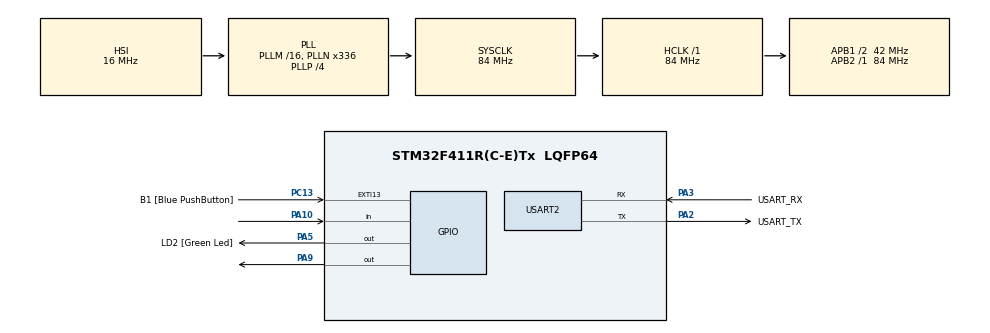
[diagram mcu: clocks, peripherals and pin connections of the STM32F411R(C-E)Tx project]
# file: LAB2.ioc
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Mcu.Family=STM32F4
Mcu.Name=STM32F411R(C-E)Tx
Mcu.Package=LQFP64
NVIC.PriorityGroup=NVIC_PRIORITYGROUP_0
PA10.Signal=GPIO_Input
PA13.GPIO_Label=TMS
PA13.Mode=Serial_Wire
PA13.Signal=SYS_JTMS-SWDIO
PA14.GPIO_Label=TCK
PA14.Mode=Serial_Wire
PA14.Signal=SYS_JTCK-SWCLK
PA2.GPIO_Label=USART_TX
PA2.Mode=Asynchronous
PA2.Signal=USART2_TX
PA3.GPIO_Label=USART_RX
PA3.Mode=Asynchronous
PA3.Signal=USART2_RX
PA5.GPIO_Label=LD2 [Green Led]
PA5.Signal=GPIO_Output
PA9.Signal=GPIO_Output
PB3.GPIO_Label=SWO
PB3.Signal=SYS_JTDO-SWO
PC13-ANTI_TAMP.GPIO_Label=B1 [Blue PushButton]
PC13-ANTI_TAMP.GPIO_ModeDefaultEXTI=GPIO_MODE_IT_FALLING
PC13-ANTI_TAMP.Signal=GPXTI13
PC14-OSC32_IN.Mode=LSE-External-Oscillator
PC14-OSC32_IN.Signal=RCC_OSC32_IN
PC15-OSC32_OUT.Mode=LSE-External-Oscillator
PC15-OSC32_OUT.Signal=RCC_OSC32_OUT
PH0\ -\ OSC_IN.Mode=HSE-External-Clock-Source
PH0\ -\ OSC_IN.Signal=RCC_OSC_IN
PH1\ -\ OSC_OUT.Mode=HSE-External-Clock-Source
PH1\ -\ OSC_OUT.Signal=RCC_OSC_OUT
ProjectManager.HeapSize=0x200
ProjectManager.StackSize=0x400
ProjectManager.TargetToolchain=STM32CubeIDE
RCC.48MHZClocksFreq_Value=84000000
RCC.AHBFreq_Value=84000000
RCC.APB1CLKDivider=RCC_HCLK_DIV2
RCC.APB1Freq_Value=42000000
RCC.APB1TimFreq_Value=84000000
RCC.APB2Freq_Value=84000000
RCC.APB2TimFreq_Value=84000000
RCC.CortexFreq_Value=84000000
RCC.FLatency-AdvancedSettings=FLASH_LATENCY_2
RCC.HCLKFreq_Value=84000000
RCC.HSE_VALUE=8000000
RCC.HSI_VALUE=16000000
RCC.PLLN=336
RCC.PLLP=RCC_PLLP_DIV4
RCC.SYSCLKFreq_VALUE=84000000
RCC.SYSCLKSource=RCC_SYSCLKSOURCE_PLLCLK
RCC.VCOOutputFreq_Value=336000000
USART2.VirtualMode=VM_ASYNC
board=NUCLEO-F411RE

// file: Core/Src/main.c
/* USER CODE BEGIN Header */
/**
 ******************************************************************************
 * @file           : main.c
 * @brief          : Main program body
 ******************************************************************************
 * @attention
 *
 * <h2><center>&copy; Copyright (c) 2021 STMicroelectronics.
 * All rights reserved.</center></h2>
 *
 * This software component is licensed by ST under BSD 3-Clause license,
 * the "License"; You may not use this file except in compliance with the
 * License. You may obtain a copy of the License at:
 *                        opensource.org/licenses/BSD-3-Clause
 *
 ******************************************************************************
 */
/* USER CODE END Header */
#include "main.h"

UART_HandleTypeDef huart2;

/* USER CODE BEGIN PV */
//save state of Button Matrix
uint16_t ButtonMatrixState = 0;

//Array Matrix
uint16_t *Array[11] = { 0 };

//Counter
uint16_t Number= 0;
uint16_t LED = 0;
//Button TimeStamp
uint32_t ButtonMatrixTimestamp = 0;
uint32_t TimeStamp = 0;

/* USER CODE END PV */

void SystemClock_Config(void);
static void MX_GPIO_Init(void);
static void MX_USART2_UART_Init(void);
/* USER CODE BEGIN PFP */
//scan and update data of Button Matrix
void ButtonMatrixUpdate();
/* USER CODE END PFP */

int main(void) {

	/* MCU Configuration--------------------------------------------------------*/

	/* Reset of all peripherals, Initializes the Flash interface and the Systick. */
	HAL_Init();

	/* Configure the system clock */
	SystemClock_Config();

	/* Initialize all configured peripherals */
	MX_GPIO_Init();
	MX_USART2_UART_Init();

	/* Infinite loop */
	while (1) {

		/* USER CODE BEGIN 3 */
		ButtonMatrixUpdate();
		if (HAL_GetTick() - TimeStamp >= 300) {

			if (ButtonMatrixState == 1) {
				Array[Number] = 7;
				TimeStamp = HAL_GetTick();
				Number += 1;
			}
			if (ButtonMatrixState == 2) {
				Array[Number] = 8;
				TimeStamp = HAL_GetTick();
				Number += 1;
			}
			if (ButtonMatrixState == 4) {
				Array[Number] = 9;
				TimeStamp = HAL_GetTick();
				Number += 1;
			}
			if (ButtonMatrixState == 16) {
				Array[Number] = 4;
				TimeStamp = HAL_GetTick();
				Number += 1;
			}
			if (ButtonMatrixState == 32) {
				Array[Number] = 5;
				TimeStamp = HAL_GetTick();
				Number += 1;
			}
			if (ButtonMatrixState == 64) {
				Array[Number] = 6;
				TimeStamp = HAL_GetTick();
				Number += 1;
			}
			if (ButtonMatrixState == 256) {
				Array[Number] = 1;
				TimeStamp = HAL_GetTick();
				Number += 1;
			}
			if (ButtonMatrixState == 512) {
				Array[Number] = 2;
				TimeStamp = HAL_GetTick();
				Number += 1;
			}
			if (ButtonMatrixState == 1024) {
				Array[Number] = 3;
				TimeStamp = HAL_GetTick();
				Number += 1;
			}
			if (ButtonMatrixState == 4096) {
				Array[Number] = 0;
				TimeStamp = HAL_GetTick();
				Number += 1;
			}
			if (ButtonMatrixState == 8) {
				Array[0] = 0;
				Array[1] = 0;
				Array[2] = 0;
				Array[3] = 0;
				Array[4] = 0;
				Array[5] = 0;
				Array[6] = 0;
				Array[7] = 0;
				Array[8] = 0;
				Array[9] = 0;
				Array[10] = 0;
				Number = 0;
				TimeStamp = HAL_GetTick();
				LED = 0;
			}
			if (ButtonMatrixState == 32768) {
				if (Array[0] == 6 && Array[1] == 2 && Array[2] == 3 && Array[3] == 4)
				{
					if (Array[4] == 0 && Array[5] == 5 && Array[6] == 0 && Array[7] == 0)
					{
						if (Array[8] == 0 && Array[9] == 4 && Array[10] == 0)
						{
							LED =1;
						}
					}
				}
			}
		}
		if(LED==1)
		{
			HAL_GPIO_WritePin(GPIOA, GPIO_PIN_5, 1);
		}
		if(LED==0)
		{
			HAL_GPIO_WritePin(GPIOA, GPIO_PIN_5, 0);
		}

	}
	/* USER CODE END 3 */
}

void SystemClock_Config(void) {
	RCC_OscInitTypeDef RCC_OscInitStruct = { 0 };
	RCC_ClkInitTypeDef RCC_ClkInitStruct = { 0 };

	/** Configure the main internal regulator output voltage
	 */
	__HAL_RCC_PWR_CLK_ENABLE();
	__HAL_PWR_VOLTAGESCALING_CONFIG(PWR_REGULATOR_VOLTAGE_SCALE1);
	/** Initializes the RCC Oscillators according to the specified parameters
	 * in the RCC_OscInitTypeDef structure.
	 */
	RCC_OscInitStruct.OscillatorType = RCC_OSCILLATORTYPE_HSI;
	RCC_OscInitStruct.HSIState = RCC_HSI_ON;
	RCC_OscInitStruct.HSICalibrationValue = RCC_HSICALIBRATION_DEFAULT;
	RCC_OscInitStruct.PLL.PLLState = RCC_PLL_ON;
	RCC_OscInitStruct.PLL.PLLSource = RCC_PLLSOURCE_HSI;
	RCC_OscInitStruct.PLL.PLLM = 16;
	RCC_OscInitStruct.PLL.PLLN = 336;
	RCC_OscInitStruct.PLL.PLLP = RCC_PLLP_DIV4;
	RCC_OscInitStruct.PLL.PLLQ = 4;
	if (HAL_RCC_OscConfig(&RCC_OscInitStruct) != HAL_OK) {
		Error_Handler();
	}
	/** Initializes the CPU, AHB and APB buses clocks
	 */
	RCC_ClkInitStruct.ClockType = RCC_CLOCKTYPE_HCLK | RCC_CLOCKTYPE_SYSCLK
			| RCC_CLOCKTYPE_PCLK1 | RCC_CLOCKTYPE_PCLK2;
	RCC_ClkInitStruct.SYSCLKSource = RCC_SYSCLKSOURCE_PLLCLK;
	RCC_ClkInitStruct.AHBCLKDivider = RCC_SYSCLK_DIV1;
	RCC_ClkInitStruct.APB1CLKDivider = RCC_HCLK_DIV2;
	RCC_ClkInitStruct.APB2CLKDivider = RCC_HCLK_DIV1;

	if (HAL_RCC_ClockConfig(&RCC_ClkInitStruct, FLASH_LATENCY_2) != HAL_OK) {
		Error_Handler();
	}
}

static void MX_USART2_UART_Init(void) {

	huart2.Instance = USART2;
	huart2.Init.BaudRate = 115200;
	huart2.Init.WordLength = UART_WORDLENGTH_8B;
	huart2.Init.StopBits = UART_STOPBITS_1;
	huart2.Init.Parity = UART_PARITY_NONE;
	huart2.Init.Mode = UART_MODE_TX_RX;
	huart2.Init.HwFlowCtl = UART_HWCONTROL_NONE;
	huart2.Init.OverSampling = UART_OVERSAMPLING_16;
	if (HAL_UART_Init(&huart2) != HAL_OK) {
		Error_Handler();
	}

}

static void MX_GPIO_Init(void) {
	GPIO_InitTypeDef GPIO_InitStruct = { 0 };

	/* GPIO Ports Clock Enable */
	__HAL_RCC_GPIOC_CLK_ENABLE();
	__HAL_RCC_GPIOH_CLK_ENABLE();
	__HAL_RCC_GPIOA_CLK_ENABLE();
	__HAL_RCC_GPIOB_CLK_ENABLE();

	/*Configure GPIO pin Output Level */
	HAL_GPIO_WritePin(GPIOA, GPIO_PIN_5, GPIO_PIN_RESET);

	/*Configure GPIO pin Output Level */
	HAL_GPIO_WritePin(GPIOA, GPIO_PIN_7 | GPIO_PIN_9, GPIO_PIN_SET);

	/*Configure GPIO pin Output Level */
	HAL_GPIO_WritePin(GPIOC, GPIO_PIN_7, GPIO_PIN_SET);

	/*Configure GPIO pin Output Level */
	HAL_GPIO_WritePin(GPIOB, GPIO_PIN_6, GPIO_PIN_SET);

	/*Configure GPIO pin : B1_Pin */
	GPIO_InitStruct.Pin = B1_Pin;
	GPIO_InitStruct.Mode = GPIO_MODE_IT_FALLING;
	GPIO_InitStruct.Pull = GPIO_NOPULL;
	HAL_GPIO_Init(B1_GPIO_Port, &GPIO_InitStruct);

	/*Configure GPIO pin : PA5 */
	GPIO_InitStruct.Pin = GPIO_PIN_5;
	GPIO_InitStruct.Mode = GPIO_MODE_OUTPUT_PP;
	GPIO_InitStruct.Pull = GPIO_NOPULL;
	GPIO_InitStruct.Speed = GPIO_SPEED_FREQ_LOW;
	HAL_GPIO_Init(GPIOA, &GPIO_InitStruct);

	/*Configure GPIO pins : PA7 PA9 */
	GPIO_InitStruct.Pin = GPIO_PIN_7 | GPIO_PIN_9;
	GPIO_InitStruct.Mode = GPIO_MODE_OUTPUT_OD;
	GPIO_InitStruct.Pull = GPIO_NOPULL;
	GPIO_InitStruct.Speed = GPIO_SPEED_FREQ_LOW;
	HAL_GPIO_Init(GPIOA, &GPIO_InitStruct);

	/*Configure GPIO pin : PC7 */
	GPIO_InitStruct.Pin = GPIO_PIN_7;
	GPIO_InitStruct.Mode = GPIO_MODE_OUTPUT_OD;
	GPIO_InitStruct.Pull = GPIO_NOPULL;
	GPIO_InitStruct.Speed = GPIO_SPEED_FREQ_LOW;
	HAL_GPIO_Init(GPIOC, &GPIO_InitStruct);

	/*Configure GPIO pin : PA10 */
	GPIO_InitStruct.Pin = GPIO_PIN_10;
	GPIO_InitStruct.Mode = GPIO_MODE_INPUT;
	GPIO_InitStruct.Pull = GPIO_PULLUP;
	HAL_GPIO_Init(GPIOA, &GPIO_InitStruct);

	/*Configure GPIO pins : PB3 PB4 PB5 */
	GPIO_InitStruct.Pin = GPIO_PIN_3 | GPIO_PIN_4 | GPIO_PIN_5;
	GPIO_InitStruct.Mode = GPIO_MODE_INPUT;
	GPIO_InitStruct.Pull = GPIO_PULLUP;
	HAL_GPIO_Init(GPIOB, &GPIO_InitStruct);

	/*Configure GPIO pin : PB6 */
	GPIO_InitStruct.Pin = GPIO_PIN_6;
	GPIO_InitStruct.Mode = GPIO_MODE_OUTPUT_OD;
	GPIO_InitStruct.Pull = GPIO_NOPULL;
	GPIO_InitStruct.Speed = GPIO_SPEED_FREQ_LOW;
	HAL_GPIO_Init(GPIOB, &GPIO_InitStruct);

}

/* USER CODE BEGIN 4 */
//port/pin array , 0-3 input , 4-7 output
GPIO_TypeDef *ButtonmatrixPort[8] = { GPIOA, GPIOB, GPIOB, GPIOB, GPIOA,
GPIOC, GPIOB, GPIOA };
uint16_t ButtonmatrixPin[8] = { GPIO_PIN_10, GPIO_PIN_3, GPIO_PIN_5,
GPIO_PIN_4, GPIO_PIN_9, GPIO_PIN_7, GPIO_PIN_6, GPIO_PIN_7 };
uint8_t ButtonMatrixRow = 0;
void ButtonMatrixUpdate() {
	if (HAL_GetTick() - ButtonMatrixTimestamp >= 50) {
		ButtonMatrixTimestamp = HAL_GetTick();
		int i;
		for (i = 0; i < 4; i++) {
			//0-3 INPUT PIN

			GPIO_PinState PinState = HAL_GPIO_ReadPin(ButtonmatrixPort[i],
					ButtonmatrixPin[i]);
			if (PinState == GPIO_PIN_RESET) // Button Press
					{
				ButtonMatrixState |= (uint16_t) 0x1
						<< (i + ButtonMatrixRow * 4);

			} else {
				ButtonMatrixState &= ~((uint16_t) 0x1
						<< (i + ButtonMatrixRow * 4));
			}
		}

		uint8_t NowOutputPin = ButtonMatrixRow + 4; // PIN OUTPUT

		// Set Rn
		HAL_GPIO_WritePin(ButtonmatrixPort[NowOutputPin],
				ButtonmatrixPin[NowOutputPin], GPIO_PIN_SET);

		// Update New Row
		ButtonMatrixRow = ((ButtonMatrixRow + 1) % 4);

		uint8_t Nextoutputpin = ButtonMatrixRow + 4;

		// Reset Rn+1
		HAL_GPIO_WritePin(ButtonmatrixPort[Nextoutputpin],
				ButtonmatrixPin[Nextoutputpin], GPIO_PIN_RESET);
	}
}
/* USER CODE END 4 */

void Error_Handler(void) {
	__disable_irq();
	while (1) {
	}
}

/************************ (C) COPYRIGHT STMicroelectronics *****END OF FILE****/
